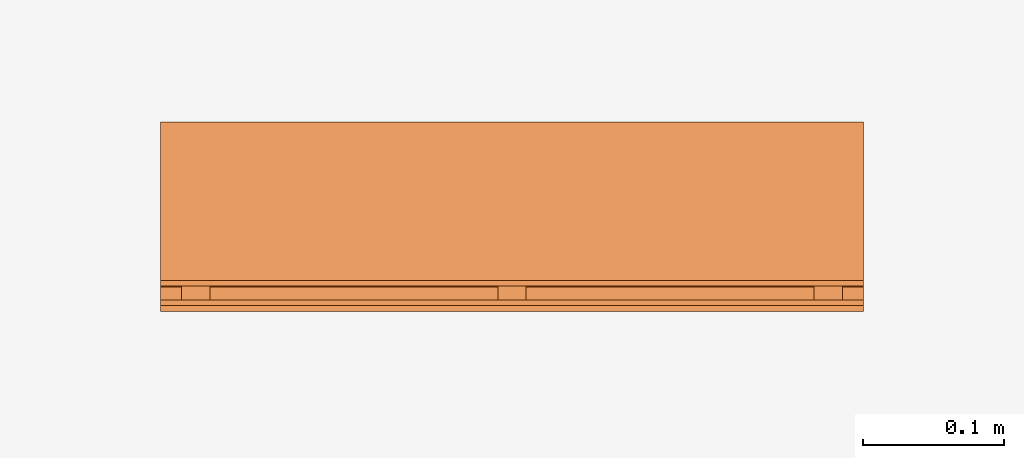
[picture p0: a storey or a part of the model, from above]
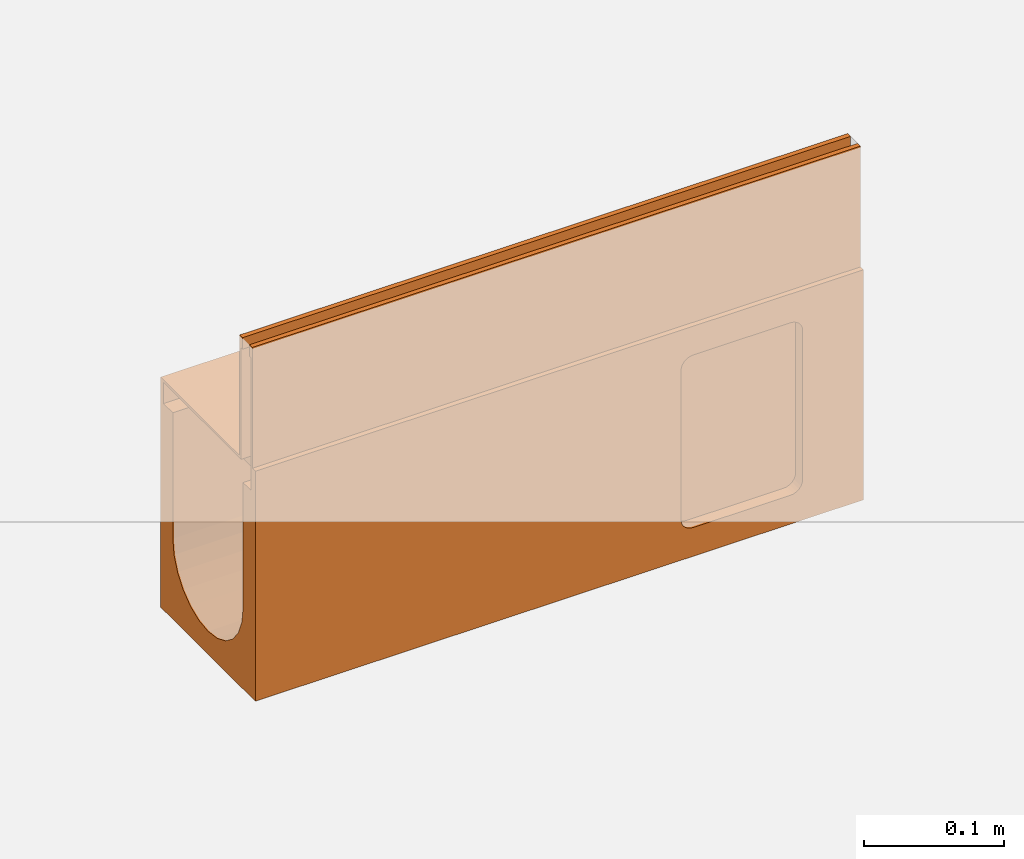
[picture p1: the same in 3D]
Properties of the parts of a building model (IFC2X3)

# File
Description: ViewDefinition [CoordinationView]
File name: 23101 - No 10.1J Constant Depth Channel - 500mm LG -Invert Depth 180mm.ifc
Time: 2013-10-31T17:32:14
Written by: Autodesk Revit 2013
Made in: 20120221_2030(x64)

# IfcProject, Project Number
LongName: Project Name; Phase: Project Status

# IfcSite, Default
RefLatitude: 42, 21, 30, 344238; RefLongitude: -71, -3, -35, -194702; RefElevation: 0 mm

# IfcBuilding
Pset_BuildingCommon - NumberOfStoreys: 1
Other - Project Number: Project Number; Project Name: Project Name; Project Issue Date: Issue Date; Project Status: Project Status; Client Name: Owner; Project Address: ## Street City, State Zip

# IfcBuildingStorey, Level 1
LongName: Level 1; Elevation: 0 mm
Graphics - Symbol: M_Level Head - Circle: M_Level Head - Circle; Color: 0; Line Weight: 1; Symbol at End 1 Default: no; Symbol at End 2 Default: yes; Line Pattern: Center
Constraints - Elevation Base: 0; Elevation: 0 mm
Dimensions - Computation Height: 0 mm
Identity Data - Name: Level 1; Structural: no; Building Story: yes

# IfcBuildingElementProxy: 23101 - No 10.1J Constant Depth Channel - 500mm LG -Invert Depth 180mm, Civil-Drainage-Channel-ACO-MultiDrain-M100D-Brickslot-Channel-System:23101 - No 10.1J Constant Depth Channel - 500mm LG -Invert Depth 180mm:23101 - No 10.1J Constant Depth Channel - 500mm LG -Invert Depth 180mm:196059
In: Level 1
Material: Steel, Galvanized, Vienite® Synthetic Resin Concrete
Dimensions - Brickslot Void Depth: 0 mm; Brickslot Access Unit Void Depth: -6500 mm; Brickslot Access Unit Void Bottom Depth: -6605 mm; FloorCut_Length: -500 mm; Volume: 4784205 mm3; Length: 1000 mm; Brickslot Void Length: 500 mm; Custom_Void_length: 500 mm; EndCap Position: 500 mm; ShallowInvDepth: 55 mm; FloorCut_Width: 135 mm; Floor Cut Gap: 105 mm; FloorCut_Depth: 200 mm; EndCap_Height: 200 mm; SlopingEndOverallDepth: 250 mm; SlopingEndInvertDepth: 180 mm; Access_Custom_Void_Length: 0 mm; GratingLength: -1000 mm; InvDepth: 130 mm; Length Drain: -500 mm; Brickslot Access Unit Floor Cut Length: 500 mm; Depth: 200 mm; SlopingOverallDepth: 245 mm; ShallowOverallDepth: 75 mm; SlopingInvertDepth: 175 mm
Construction - 23466_Load Class D400_Brickslot Grating_Galvanized Steel_500mm Long: yes; 23461_Load Class C250_Brickslot Grating_Galvanized Steel_500mm Long: no; 23462_Load Class C250_Brickslot Access Unit_Galvanised Steel_500mm Long: no; 23460_Load Class C250_Brickslot Grating_Galvanized Steel_1000mm Long: no; 23465_Load Class D400_Brickslot Grating_Galvanized Steel_1000mm Long: no; 23467_Load Class D400_Brickslot Access Unit_Galvanised Steel_500mm Long: no; 23404_Universal Endcap (Male End): no; 23404_Universal Endcap (Female End): no; Constant Depth Junction Channel: yes; Sloping Channel: no; 23410_Sump Unit: no; Shallow Depth Channel: no; Constant Depth Channel: no; Shallow Depth Channel with seal: no
Phasing - Phase Created: New Construction
Constraints - Level: Level: Level 1; Moves With Nearby Elements: no
Pset_BuildingElementProxyCommon - Reference: 23101 - No 10.1J Constant Depth Channel - 500mm LG -Invert Depth 180mm
Model Properties - Brickslot Grating Product code 23460: N/A; Brickslot Access Unit Product code 23467: Load Class D400 - Brickslot Access Unit Galvanised Steel - 500mm long x 105mm high - 10mm Slot - Intake area - 10000mm²/m - 6.4 Kg; Brickslot Grating Product code 23465: N/A; End Cap Product code 23404: No 306 Universal End Cap - 135mm wide x 300mm long - Spigot Ø110mm x 50mm long - Silver - Polypropylene - 0.16kg; Brickslot Grating Product code 23466: Load Class D400 - Brickslot Galvanised Steel - 500mm long x 105mm high - 10mm Slot - Intake area - 10000mm²/m - 3.3 Kg; Brickslot Access Unit Product code 23462: Load Class C250 - Brickslot Access Unit Galvanised Steel - 500mm long x 105mm high - 10mm Slot - Intake area - 10000mm²/m - 6.4 Kg; Brickslot Grating Product code 23461: Load Class C250 - Brickslot Galvanised Steel - 500mm long x 105mm high - 10mm Slot - Intake area - 10000mm²/m -3.3 Kg
Identity Data - Assembly Code: D2040; Cost: 0; Watermark 2: This file is water marked and users are prohibited to reproduce, adapt, distribute this information; OmniClass Number: 23.70.50.24; Fax: +44 (0)1462 815895; Telephone: +44 (0)1462 816666; URL: www.aco.co.uk; Product brochure: http://www.aco.co.uk/download.php?id=173; Installation guidelines: http://www.aco.co.uk/download.php?id=173; Assembly Description: Rain Water Drainage; Maintenance guidelines: http://www.aco.co.uk/download.php?id=173; Model Description: Channel drainage system; Watermark 1: This file is the property of ACO Technologies PLC; e-mail Technical: technical@aco.co.uk; Watermarked With: BIM Manager Premium Suite; Address: ACO Business Park, Hitchin Road, Shefford, Bedfordshire, United Kingdom SG17 5TE; Price: POA - contact ACO; Manufacturer: ACO Technologies plc - ACO Water Management Division; Product Page URL: http://www.aco.co.uk/product_detail.php?id=58; Type Comments: ACO MultiDrain M100D 10.1J Constant Depth Junction Channel 500mm Long; e-mail Sales: customersupport@aco.co.uk; OmniClass Title: Rainwater Removal; Product Code: 23101; Model: ACO MultiDrain MD Brickslot- M100D
Other - Created By: www.aco.co.uk; Watermarked By: www.aco.co.uk; Revision: 1
Data - ACO Hydraulic Design Software: http://www.acodesign.co.uk; Load Class: A 15 - D 400; Product Standard: BS EN 1433:2002, CE marked; Concrete Surround Volume - Load Class B 125 - C 250 - Concrete Pavement: 0.13m³/m; Channel C.S.A: 0.013m²; Concrete Surround Volume - Load Class D 400 - Concrete Pavement: 0.19m³/m; Hydraulic Performance: http://www.aco.co.uk/download.php?id=173; Concrete Surround Volume - Load Class A 15 - Concrete Pavement: 0.08m³/m; Invert Depth: 180mm; Pre-formed Outlet Ø: N/A; Product Dimensions: 500mm x 135mm x 200mm (LxWxH); Product Weight: 9.2 Kg; Installation - Concrete Grade: Refer to brochure
Green Building Properties - Edge Rail Recycled Material Content: Between 40% - 90%; Channel Recycled Material Content: 20% minimum; Channel Recyclable: Fully recyclable; Edge Rail Recyclable: Fully recyclable
General - SerialNumber: 0; TagNumber: 0
Materials and Finishes - Edge Rail Finish: Pre-galvanised; Channel Colour: Brown; Edge Rail Colour: Silver; Channel Material: Vienite® Synthetic Resin Concrete; Edge Rail Material: Steel

# IfcOpeningElement: Recess (2)
In: Level 1
Structural - Enable Analytical Model: no; Structural: no
Dimensions - Volume: 24985555000 mm3; Perimeter: 20000 mm; Area: 25000000 mm2; Thickness: 1000 mm
Constraints - Related to Mass: no; Height Offset From Level: 0 mm; Room Bounding: yes; Level: Level: Level 1
Phasing - Phase Created: New Construction
Construction - Function: 0; Default Thickness: 1000 mm
Materials and Finishes - Structural Material: Earth
Analytical Properties - Thermal mass: 1359800; Roughness: 1; Absorptance: 0.1; Thermal Resistance (R): 1.19474; Heat Transfer Coefficient (U): 0.837
Graphics - Coarse Scale Fill Color: 0

# IfcSlab: Floor:Generic Floor - 1000mm, Floor:Generic Floor - 1000mm:193825
In: Level 1
PredefinedType: FLOOR; Material: Earth 1000 mm
Structural - Enable Analytical Model: no; Structural: no
Dimensions - Volume: 24985555000 mm3; Perimeter: 20000 mm; Area: 25000000 mm2; Thickness: 1000 mm
Constraints - Related to Mass: no; Height Offset From Level: 0 mm; Room Bounding: yes; Level: Level: Level 1
Phasing - Phase Created: New Construction
Pset_SlabCommon - Reference: Generic Floor - 1000mm; IsExternal: no; LoadBearing: yes
Construction - Function: 0; Default Thickness: 1000 mm
Materials and Finishes - Structural Material: Earth
Analytical Properties - Thermal mass: 1359800; Roughness: 1; Absorptance: 0.1; Thermal Resistance (R): 1.19474; Heat Transfer Coefficient (U): 0.837
Graphics - Coarse Scale Fill Color: 0
